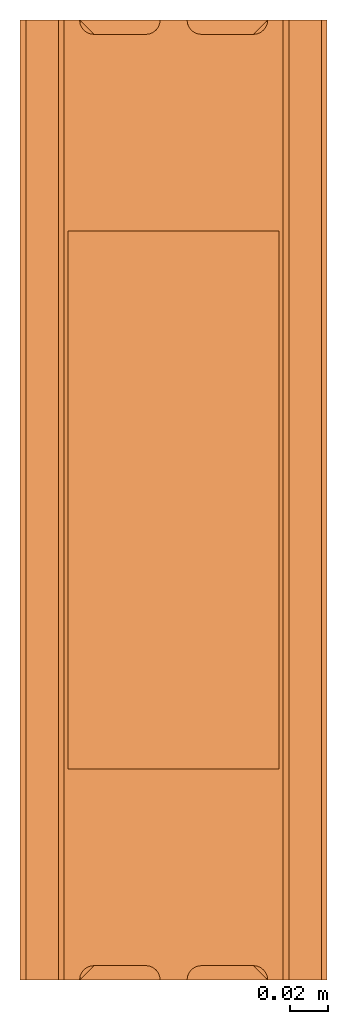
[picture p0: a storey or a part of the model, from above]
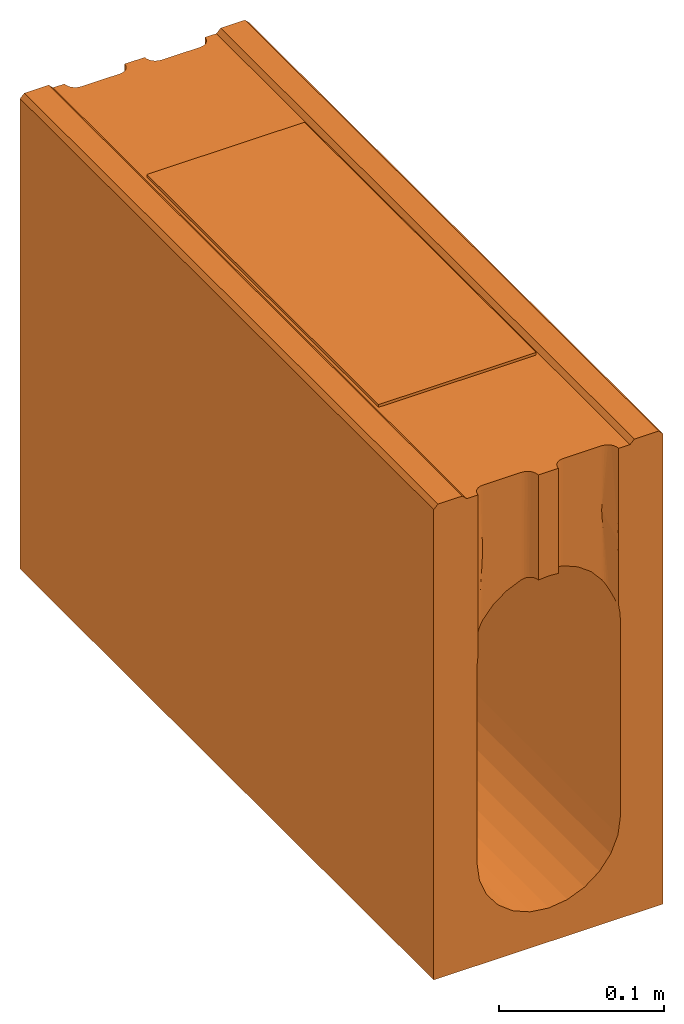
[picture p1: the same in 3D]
Properties of the parts of a building model (IFC2X3)

# File
Description: ViewDefinition [CoordinationView]
File name: 32303 - PD100 F 30.3 Rodding Access 500mm LG.ifc
Time: 2013-10-11T12:31:38
Written by: Autodesk Revit 2013
Made in: 20120221_2030(x64)

# IfcProject, Project Number
LongName: Project Name; Phase: Project Status

# IfcSite, Default
RefLatitude: 42, 21, 30, 344238; RefLongitude: -71, -3, -35, -194702; RefElevation: 0 mm

# IfcBuilding
Pset_BuildingCommon - NumberOfStoreys: 2
Other - Project Number: Project Number; Project Status: Project Status; Project Issue Date: Issue Date; Project Address: Enter address here; Client Name: Owner; Project Name: Project Name

# IfcBuildingStorey (2)
Constraints - Elevation Base: 0
Graphics - Line Pattern: Center; Color: 0; Symbol: M_Level Head - Circle: M_Level Head - Circle; Symbol at End 1 Default: no; Line Weight: 1; Symbol at End 2 Default: yes
Dimensions - Computation Height: 0 mm
Identity Data - Building Story: yes; Structural: no
Name | LongName = Name | Elevation (mm) = Constraints, Elevation (mm)
B.O. Footing | B.O. Footing | -4600
T.O. Footing | T.O. Footing | -4300

# IfcBuildingElementProxy: 32303 - PD100 F 30.3 Rodding Access 500mm LG, Civil-Drainage-Channel-ACO-RoadDrain 100:32303 - PD100 F 30.3 Rodding Access 500mm LG:32303 - PD100 F 30.3 Rodding Access 500mm LG:310733
In: B.O. Footing
Material: Acetal Resin, Black
Other - Revision: 1; CreatedBy: www.aco.co.uk
Construction - 32900 - Sump Unit: no; Inlet Outlet end cap_450 high: no; Access unit: yes; Closing End Cap: no; Channel 160mm Wide: no; Inlet Outlet end cap_350 high: no; Grating 500mm: no
Dimensions - Total Depth: 350 mm; Void Depth: -350 mm; Straight Void Start: 0 mm; I/O End Cap Void: 3500 mm; Invert Depth.: 275 mm; Volume: 16568460 mm3; Custom Void Length: 0 mm; Straight Void Length: 500 mm; Length: 500 mm
Phasing - Phase Created: Phase 1
Constraints - Moves With Nearby Elements: no; Level: Level: T.O. Footing
Pset_BuildingElementProxyCommon - Reference: 32303 - PD100 F 30.3 Rodding Access 500mm LG
Data - ACO Hydraulic Design Software: http://www.acodesign.co.uk; Product Dimensions: 500mm x 160mm x 350mm (LxWxH); Concrete Surround Volume - Load Class F 900 - Concrete Pavement: 0.26m³; Product Weight: 31.0 Kg; Product Standard: BE EN1433:2002, CE Marked, Kitemarked; Installation - Concrete Grade: Refer to brochure; Channel C.S.A: 0.022m²; Invert Depth: 325mm; Load Class: A 15 - F 900; Connection Pipe O.D: N/A; Hydraulic Performance: http://www.aco.co.uk/download.php?id=256
Identity Data - Product brochure: http://www.aco.co.uk/download.php?id=256; Installation guidelines: http://www.aco.co.uk/download.php?id=256; e-mail Technical: technical@aco.co.uk; Product Code: 32303; Cost: 0; URL: www.aco.co.uk; Model: ACO RoadDrain 100 PD100F; Maintenance guidelines: http://www.aco.co.uk/download.php?id=256; Assembly Description: Rain Water Drainage; Watermark 1: This file is the property of ACO Technologies PLC; Manufacturer: ACO Technologies plc - ACO Water Management Division; Watermarked With: BIM Manager Premium Suite; Watermarked By: www.aco.co.uk; Product Page URL: http://www.aco.co.uk/product_detail.php?id=21; Watermark 2: This file is water marked and users are prohibited to reproduce, adapt, distribute this information; OmniClass Number: 23.70.50.24; Address: ACO Business Park, Hitchin Road, Shefford, Bedfordshire, United Kingdom SG17 5TE; Model Description: Monolithic Channel drainage system; OmniClass Title: Rainwater Removal; Fax: +44 (0)1462 815895; Price: POA - contact ACO; e-mail Sales: customersupport@aco.co.uk; Type Comments: ACO RoadDrain 100 PD100F 30.3 Constant Depth Access Channel 500mm Long; Telephone: +44 (0)1462 816666; Assembly Code: D2040
Green Building Properties - Channel Recycled Material Content: 20% minimum; Access Cover/Frame Recyclable: Fully recyclable; Access Cover/Frame Recycled Material Content: Between 40% - 90%; Grating Recycled Material Content: N/A; Grating Recyclable: N/A; Channel Recyclable: Fully recyclable; End Cap Recyclable: N/A; End Cap Recycled Material Content: N/A
General - TagNumber: 0.000000; SerialNumber: 0.000000
Materials and Finishes - Connection Pipe Material: N/A; End Cap Colour: N/A; Grating Colour: N/A; Channel Material: Vienite® Synthetic Resin Concrete; Access Cover/Frame Colour: Black; Channel Colour: Black; Access Cover/Frame Material: Ductile Iron; Grating Finish: N/A; Access Cover/Frame Finish: Water Based Paint Coating; Grating Material: N/A; End Cap Material: N/A; Connection Pipe Colour: N/A

# IfcOpeningElement: Recess (2)
In: T.O. Footing
Dimensions - Perimeter: 22200 mm; Volume: 47712000000 mm3; Area: 30800000 mm2; Thickness: 1550 mm
Constraints - Related to Mass: no; Room Bounding: yes; Height Offset From Level: 0 mm; Level: Level: T.O. Footing
Structural - Enable Analytical Model: no; Structural: no
Phasing - Phase Created: Phase 1
Construction - Function: 0; Default Thickness: 1550 mm
Analytical Properties - Absorptance: 0.1; Thermal Resistance (R): 1.79211; Roughness: 1; Heat Transfer Coefficient (U): 0.558; Thermal mass: 2039700
Graphics - Coarse Scale Fill Color: 0
Materials and Finishes - Structural Material: Grass

# IfcSlab: Floor:Generic Floor - 400mm, Floor:Generic Floor - 400mm:136436
In: T.O. Footing
PredefinedType: FLOOR; Material: Grass 50 mm, Earth 1500 mm
Dimensions - Perimeter: 22200 mm; Volume: 47712000000 mm3; Area: 30800000 mm2; Thickness: 1550 mm
Constraints - Related to Mass: no; Room Bounding: yes; Height Offset From Level: 0 mm; Level: Level: T.O. Footing
Structural - Enable Analytical Model: no; Structural: no
Phasing - Phase Created: Phase 1
Pset_SlabCommon - Reference: Generic Floor - 400mm; IsExternal: no; LoadBearing: yes
Construction - Function: 0; Default Thickness: 1550 mm
Analytical Properties - Absorptance: 0.1; Thermal Resistance (R): 1.79211; Roughness: 1; Heat Transfer Coefficient (U): 0.558; Thermal mass: 2039700
Graphics - Coarse Scale Fill Color: 0
Materials and Finishes - Structural Material: Grass
